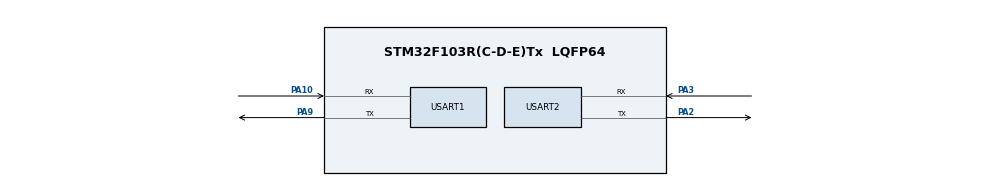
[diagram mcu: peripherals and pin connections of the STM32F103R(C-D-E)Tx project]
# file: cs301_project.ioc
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Mcu.Family=STM32F1
Mcu.Name=STM32F103R(C-D-E)Tx
Mcu.Package=LQFP64
NVIC.PriorityGroup=NVIC_PRIORITYGROUP_2
NVIC.USART1_IRQn=true\:0\:0\:false\:false\:true\:true\:true
NVIC.USART2_IRQn=true\:0\:0\:false\:false\:true\:true\:true
PA10.Mode=Asynchronous
PA10.Signal=USART1_RX
PA2.Mode=Asynchronous
PA2.Signal=USART2_TX
PA3.Mode=Asynchronous
PA3.Signal=USART2_RX
PA9.Mode=Asynchronous
PA9.Signal=USART1_TX
PD0-OSC_IN.Mode=HSE-External-Oscillator
PD0-OSC_IN.Signal=RCC_OSC_IN
PD1-OSC_OUT.Mode=HSE-External-Oscillator
PD1-OSC_OUT.Signal=RCC_OSC_OUT
ProjectManager.HeapSize=0x200
ProjectManager.StackSize=0x400
ProjectManager.TargetToolchain=STM32CubeIDE
RCC.APB1Freq_Value=8000000
RCC.APB2Freq_Value=8000000
USART1.VirtualMode=VM_ASYNC
USART2.VirtualMode=VM_ASYNC
VP_SYS_VS_ND.Mode=No_Debug
board=custom

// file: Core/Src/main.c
/* USER CODE BEGIN Header */
/**
  ******************************************************************************
  * @file           : main.c
  * @brief          : Main program body
  ******************************************************************************
  * @attention
  *
  * <h2><center>&copy; Copyright (c) 2021 STMicroelectronics.
  * All rights reserved.</center></h2>
  *
  * This software component is licensed by ST under BSD 3-Clause license,
  * the "License"; You may not use this file except in compliance with the
  * License. You may obtain a copy of the License at:
  *                        opensource.org/licenses/BSD-3-Clause
  *
  ******************************************************************************
  */
/* USER CODE END Header */
#include "main.h"

UART_HandleTypeDef huart1;
UART_HandleTypeDef huart2;

/* USER CODE BEGIN PV */
uint8_t rxBuffer1[1 << 8];
uint8_t rxBuffer2[1 << 8];

unsigned char* wifista_ssid="ALIENTEK";
unsigned char* wifista_encryption="wpawpa2_aes";
unsigned char* wifista_password="12345678";

unsigned char* wifiap_ssid="ALIENTEK"; //对外 SSID 号
unsigned char* wifiap_encryption="wpawpa2_aes"; //wpa/wpa2 aes 加密方式
unsigned char* wifiap_password="12345678";
/* USER CODE END PV */

void SystemClock_Config(void);
static void MX_GPIO_Init(void);
static void MX_USART1_UART_Init(void);
static void MX_USART2_UART_Init(void);

/* USER CODE BEGIN 0 */

void send_cmd(unsigned char *cmd) {
	HAL_Delay(50);
	unsigned char cmd_msg[100];
	sprintf(cmd_msg, "%s\r\n", cmd);
	HAL_UART_Transmit(&huart2, cmd_msg, strlen(cmd_msg), 0xffff);
}
void sta_connect(void)
{
	unsigned char msg[100];
	send_cmd("AT+CWMODE=1");
	send_cmd("AT+RST");
	HAL_Delay(3000);
	sprintf((char*)msg,"AT+CWJAP=\"%s\",\"%s\"",wifista_ssid,wifista_password);
	send_cmd(msg);
	HAL_Delay(1000);
	send_cmd("AT+CIPMUX=1");
	HAL_Delay(1000);
	send_cmd("AT+CIPSERVER=1,8086");
	HAL_Delay(1000);

}

void ap_connect(void){
	unsigned char msg[100];
	send_cmd("AT+CWMODE=2");
	send_cmd("AT+RST");
	HAL_Delay(3000);
	sprintf((char*)msg,"AT+CWSAP=\"%s\",\"%s\",1,4",wifiap_ssid,wifiap_password);
	send_msg(msg);
	HAL_Delay(1000);
	send_cmd("AT+CIPMUX=1");
	HAL_Delay(1000);
	send_cmd("AT+CIPSERVER=1,8086");
	HAL_Delay(1000);
}

/* USER CODE END 0 */

int main(void)
{

  /* MCU Configuration--------------------------------------------------------*/

  /* Reset of all peripherals, Initializes the Flash interface and the Systick. */
  HAL_Init();

  /* Configure the system clock */
  SystemClock_Config();

  /* Initialize all configured peripherals */
  MX_GPIO_Init();
  MX_USART1_UART_Init();
  MX_USART2_UART_Init();
  /* USER CODE BEGIN 2 */
  sta_connect();
//  ap_connect()
  /* USER CODE END 2 */

  /* Infinite loop */
  while (1)
  {

  }
}

void SystemClock_Config(void)
{
  RCC_OscInitTypeDef RCC_OscInitStruct = {0};
  RCC_ClkInitTypeDef RCC_ClkInitStruct = {0};

  /** Initializes the RCC Oscillators according to the specified parameters
  * in the RCC_OscInitTypeDef structure.
  */
  RCC_OscInitStruct.OscillatorType = RCC_OSCILLATORTYPE_HSE;
  RCC_OscInitStruct.HSEState = RCC_HSE_ON;
  RCC_OscInitStruct.HSEPredivValue = RCC_HSE_PREDIV_DIV1;
  RCC_OscInitStruct.HSIState = RCC_HSI_ON;
  RCC_OscInitStruct.PLL.PLLState = RCC_PLL_ON;
  RCC_OscInitStruct.PLL.PLLSource = RCC_PLLSOURCE_HSE;
  RCC_OscInitStruct.PLL.PLLMUL = RCC_PLL_MUL9;
  if (HAL_RCC_OscConfig(&RCC_OscInitStruct) != HAL_OK)
  {
    Error_Handler();
  }
  /** Initializes the CPU, AHB and APB buses clocks
  */
  RCC_ClkInitStruct.ClockType = RCC_CLOCKTYPE_HCLK|RCC_CLOCKTYPE_SYSCLK
                              |RCC_CLOCKTYPE_PCLK1|RCC_CLOCKTYPE_PCLK2;
  RCC_ClkInitStruct.SYSCLKSource = RCC_SYSCLKSOURCE_PLLCLK;
  RCC_ClkInitStruct.AHBCLKDivider = RCC_SYSCLK_DIV1;
  RCC_ClkInitStruct.APB1CLKDivider = RCC_HCLK_DIV2;
  RCC_ClkInitStruct.APB2CLKDivider = RCC_HCLK_DIV1;

  if (HAL_RCC_ClockConfig(&RCC_ClkInitStruct, FLASH_LATENCY_2) != HAL_OK)
  {
    Error_Handler();
  }
}

static void MX_USART1_UART_Init(void)
{

  huart1.Instance = USART1;
  huart1.Init.BaudRate = 115200;
  huart1.Init.WordLength = UART_WORDLENGTH_8B;
  huart1.Init.StopBits = UART_STOPBITS_1;
  huart1.Init.Parity = UART_PARITY_NONE;
  huart1.Init.Mode = UART_MODE_TX_RX;
  huart1.Init.HwFlowCtl = UART_HWCONTROL_NONE;
  huart1.Init.OverSampling = UART_OVERSAMPLING_16;
  if (HAL_UART_Init(&huart1) != HAL_OK)
  {
    Error_Handler();
  }

}

static void MX_USART2_UART_Init(void)
{

  huart2.Instance = USART2;
  huart2.Init.BaudRate = 115200;
  huart2.Init.WordLength = UART_WORDLENGTH_8B;
  huart2.Init.StopBits = UART_STOPBITS_1;
  huart2.Init.Parity = UART_PARITY_NONE;
  huart2.Init.Mode = UART_MODE_TX_RX;
  huart2.Init.HwFlowCtl = UART_HWCONTROL_NONE;
  huart2.Init.OverSampling = UART_OVERSAMPLING_16;
  if (HAL_UART_Init(&huart2) != HAL_OK)
  {
    Error_Handler();
  }

}

static void MX_GPIO_Init(void)
{

  /* GPIO Ports Clock Enable */
  __HAL_RCC_GPIOD_CLK_ENABLE();
  __HAL_RCC_GPIOA_CLK_ENABLE();

}

/* USER CODE BEGIN 4 */

void HAL_UART_RxCpltCallback(UART_HandleTypeDef *huart)
{
	if (huart->Instance == USART1)
	{
		static unsigned char uRx_Data1[1024] = { 0 };
		static unsigned char uLength1 = 0;
		unsigned char msg[100];
		if(rxBuffer1[0] == '\n'){
			sprintf(msg, "AT+CIPSEND=0,%d", uLength1);
			send_cmd(msg);
			send_cmd(uRx_Data1);
			uLength1 = 0;
			for (int i = 0; i < 1024; i++) {
				uRx_Data1[i] = '\0';
			}
		}else{
			uRx_Data1[uLength1] = rxBuffer1[0];
			uLength1++;
		}
	}
	else
	{
		static unsigned char uRx_Data2[1024] = { 0 };
		static unsigned char uLength2 = 0;
		if(rxBuffer2[0] == '\n'){
			HAL_UART_Transmit(&huart1, uRx_Data2, uLength2, 0xffff);
			uLength2 = 0;
			for (int i = 0; i < 1024; i++) {
				uRx_Data2[i] = '\0';
			}
		}else{
			uRx_Data2[uLength2] = rxBuffer2[0];
			uLength2++;
		}

	}
}

/* USER CODE END 4 */

void Error_Handler(void)
{
  __disable_irq();
  while (1)
  {
  }
}

/************************ (C) COPYRIGHT STMicroelectronics *****END OF FILE****/
